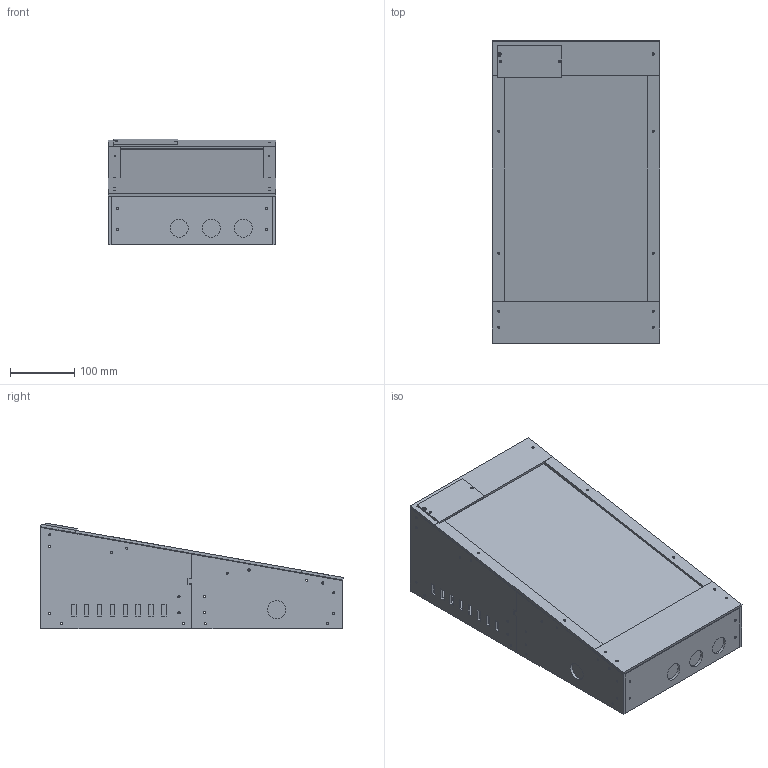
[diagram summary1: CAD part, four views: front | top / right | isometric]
STEP (ISO 10303-21) file: header records copied from the file, then geometry measured from it (millimetres).
FILE_DESCRIPTION(('Open CASCADE Model'),'2;1');
FILE_NAME('Open CASCADE Shape Model','2026-10-30T01:53:43',('Author'),( 'Open CASCADE'),'Open CASCADE STEP processor 7.8','Open CASCADE 7.8' ,'Unknown');
FILE_SCHEMA(('AUTOMOTIVE_DESIGN { 1 0 10303 214 1 1 1 1 }'));
Length unit declared in the file: millimetre
Products named in the file (55): Mini_VPin_Prototype_V1_3; left_front_wall; left_rear_wall; right_front_wall; right_rear_wall; front_button_panel; rear_vent_panel; corner_left_front_24; corner_left_front_56; corner_left_rear_24; corner_left_rear_128; corner_right_front_24; corner_right_front_56; corner_right_rear_24; corner_right_rear_128; splice_left; splice_right; floor_block_left_28; floor_block_left_218; floor_block_left_252; floor_block_left_442; floor_block_right_28; floor_block_right_218; floor_block_right_252; floor_block_right_442; bottom_front; bottom_rear; top_block_left_25; top_block_left_50; top_block_left_140; top_block_left_330; top_block_left_450; top_block_right_25; top_block_right_50; top_block_right_140; top_block_right_330; top_block_right_450; monitor_saddle_left_180; monitor_saddle_left_360; monitor_saddle_right_180 ...
Assembly tree (54 placements, depth 2):
  Mini_VPin_Prototype_V1_3
    left_front_wall
    left_rear_wall
    right_front_wall
    right_rear_wall
    front_button_panel
    rear_vent_panel
    corner_left_front_24
    corner_left_front_56
    corner_left_rear_24
    corner_left_rear_128
    corner_right_front_24
    corner_right_front_56
    corner_right_rear_24
    corner_right_rear_128
    splice_left
    splice_right
    floor_block_left_28
    floor_block_left_218
    floor_block_left_252
    floor_block_left_442
    floor_block_right_28
    floor_block_right_218
    floor_block_right_252
    floor_block_right_442
    bottom_front
    bottom_rear
    top_block_left_25
    top_block_left_50
    top_block_left_140
    top_block_left_330
    top_block_left_450
    top_block_right_25
    top_block_right_50
    top_block_right_140
    top_block_right_330
    top_block_right_450
    monitor_saddle_left_180
    monitor_saddle_left_360
    monitor_saddle_right_180
    monitor_saddle_right_360
    bezel_left_one_piece
    bezel_right_a1_a2
    front_cable_lid
    rear_control_deck
    control_hatch
    REFERENCE_monitor_12mm_envelope
    REFERENCE_PC_allowance_ports_face_front
    REFERENCE_0_front_button_110
    REFERENCE_1_front_button_160
    REFERENCE_2_front_button_210
    REFERENCE_3_left_flipper
    REFERENCE_4_right_flipper
    REFERENCE_5_central_folded_cover_reserve
    REFERENCE_6_USB_encoder_allowance
Bounding box: 260 x 470.69 x 164.59 mm (x, y, z)
Volume: 6493343.1 mm3; surface area: 1288117.8 mm2
Topology: 54 solids, 54 shells, 789 faces, 2001 edges, 1334 vertices
Faces by surface type: plane 651, cylinder 138
Full cylindrical faces by diameter (mm): 3.4 x132, 28 x5
Entity records: 51330 total; most frequent: CARTESIAN_POINT 9271, DIRECTION 7328, LINE 4793, VECTOR 4793, ORIENTED_EDGE 4002, PCURVE 4002, DEFINITIONAL_REPRESENTATION 4002, EDGE_CURVE 2001
One B-rep face of a CAD part: STEP entity #52242.
In plain terms, the planar face has unit normal (0, -0.174, 0.985).
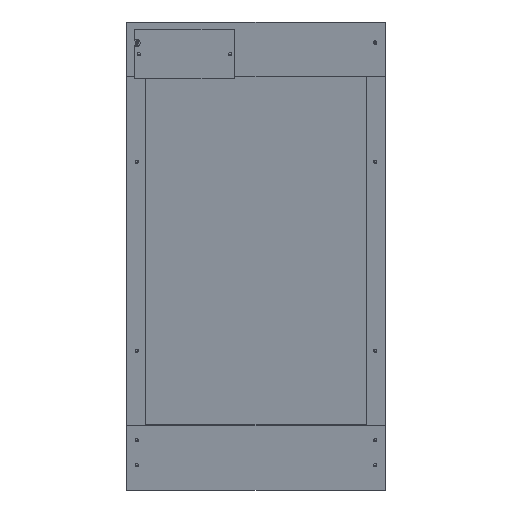
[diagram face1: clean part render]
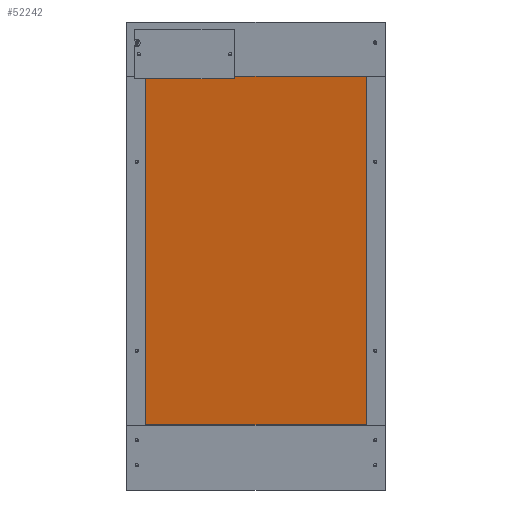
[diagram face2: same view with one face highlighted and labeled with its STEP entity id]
Its self-contained STEP definition (entity closure, numbers rounded to 3 decimals):
#52073 = PLANE('',#52074);
#52074 = AXIS2_PLACEMENT_3D('',#52075,#52076,#52077);
#52075 = CARTESIAN_POINT('',(18.1,64.,86.285));
#52076 = DIRECTION('',(-0.,1.,0.));
#52077 = DIRECTION('',(0.,0.,-1.));
#52101 = PLANE('',#52102);
#52102 = AXIS2_PLACEMENT_3D('',#52103,#52104,#52105);
#52103 = CARTESIAN_POINT('',(241.9,240.675,111.437));
#52104 = DIRECTION('',(1.,0.,0.));
#52105 = DIRECTION('',(-0.,0.,1.));
#52129 = PLANE('',#52130);
#52130 = AXIS2_PLACEMENT_3D('',#52131,#52132,#52133);
#52131 = CARTESIAN_POINT('',(18.1,417.349,136.59));
#52132 = DIRECTION('',(0.,-1.,0.));
#52133 = DIRECTION('',(0.,0.,1.));
#52155 = PLANE('',#52156);
#52156 = AXIS2_PLACEMENT_3D('',#52157,#52158,#52159);
#52157 = CARTESIAN_POINT('',(18.1,240.675,111.437));
#52158 = DIRECTION('',(1.,0.,0.));
#52159 = DIRECTION('',(-0.,0.,1.));
#52172 = VERTEX_POINT('',#52173);
#52173 = CARTESIAN_POINT('',(241.9,417.349,148.59));
#52194 = EDGE_CURVE('',#52195,#52172,#52197,.T.);
#52195 = VERTEX_POINT('',#52196);
#52196 = CARTESIAN_POINT('',(18.1,417.349,148.59));
#52197 = SURFACE_CURVE('',#52198,(#52202,#52209),.PCURVE_S1.);
#52198 = LINE('',#52199,#52200);
#52199 = CARTESIAN_POINT('',(18.1,417.349,148.59));
#52200 = VECTOR('',#52201,1.);
#52201 = DIRECTION('',(1.,0.,0.));
#52202 = PCURVE('',#52129,#52203);
#52203 = DEFINITIONAL_REPRESENTATION('',(#52204),#52208);
#52204 = LINE('',#52205,#52206);
#52205 = CARTESIAN_POINT('',(12.,0.));
#52206 = VECTOR('',#52207,1.);
#52207 = DIRECTION('',(0.,-1.));
#52208 = ( GEOMETRIC_REPRESENTATION_CONTEXT(2) 
PARAMETRIC_REPRESENTATION_CONTEXT() REPRESENTATION_CONTEXT('2D SPACE',''
  ) );
#52209 = PCURVE('',#52210,#52215);
#52210 = PLANE('',#52211);
#52211 = AXIS2_PLACEMENT_3D('',#52212,#52213,#52214);
#52212 = CARTESIAN_POINT('',(18.1,417.349,148.59));
#52213 = DIRECTION('',(0.,0.174,-0.985));
#52214 = DIRECTION('',(0.,-0.985,-0.174));
#52215 = DEFINITIONAL_REPRESENTATION('',(#52216),#52220);
#52216 = LINE('',#52217,#52218);
#52217 = CARTESIAN_POINT('',(0.,0.));
#52218 = VECTOR('',#52219,1.);
#52219 = DIRECTION('',(0.,-1.));
#52220 = ( GEOMETRIC_REPRESENTATION_CONTEXT(2) 
PARAMETRIC_REPRESENTATION_CONTEXT() REPRESENTATION_CONTEXT('2D SPACE',''
  ) );
#52242 = ADVANCED_FACE('',(#52243),#52210,.F.);
#52243 = FACE_BOUND('',#52244,.F.);
#52244 = EDGE_LOOP('',(#52245,#52246,#52269,#52292));
#52245 = ORIENTED_EDGE('',*,*,#52194,.T.);
#52246 = ORIENTED_EDGE('',*,*,#52247,.T.);
#52247 = EDGE_CURVE('',#52172,#52248,#52250,.T.);
#52248 = VERTEX_POINT('',#52249);
#52249 = CARTESIAN_POINT('',(241.9,64.,86.285));
#52250 = SURFACE_CURVE('',#52251,(#52255,#52262),.PCURVE_S1.);
#52251 = LINE('',#52252,#52253);
#52252 = CARTESIAN_POINT('',(241.9,417.349,148.59));
#52253 = VECTOR('',#52254,1.);
#52254 = DIRECTION('',(0.,-0.985,-0.174));
#52255 = PCURVE('',#52210,#52256);
#52256 = DEFINITIONAL_REPRESENTATION('',(#52257),#52261);
#52257 = LINE('',#52258,#52259);
#52258 = CARTESIAN_POINT('',(0.,-223.8));
#52259 = VECTOR('',#52260,1.);
#52260 = DIRECTION('',(1.,0.));
#52261 = ( GEOMETRIC_REPRESENTATION_CONTEXT(2) 
PARAMETRIC_REPRESENTATION_CONTEXT() REPRESENTATION_CONTEXT('2D SPACE',''
  ) );
#52262 = PCURVE('',#52101,#52263);
#52263 = DEFINITIONAL_REPRESENTATION('',(#52264),#52268);
#52264 = LINE('',#52265,#52266);
#52265 = CARTESIAN_POINT('',(37.152,-176.675));
#52266 = VECTOR('',#52267,1.);
#52267 = DIRECTION('',(-0.174,0.985));
#52268 = ( GEOMETRIC_REPRESENTATION_CONTEXT(2) 
PARAMETRIC_REPRESENTATION_CONTEXT() REPRESENTATION_CONTEXT('2D SPACE',''
  ) );
#52269 = ORIENTED_EDGE('',*,*,#52270,.F.);
#52270 = EDGE_CURVE('',#52271,#52248,#52273,.T.);
#52271 = VERTEX_POINT('',#52272);
#52272 = CARTESIAN_POINT('',(18.1,64.,86.285));
#52273 = SURFACE_CURVE('',#52274,(#52278,#52285),.PCURVE_S1.);
#52274 = LINE('',#52275,#52276);
#52275 = CARTESIAN_POINT('',(18.1,64.,86.285));
#52276 = VECTOR('',#52277,1.);
#52277 = DIRECTION('',(1.,0.,0.));
#52278 = PCURVE('',#52210,#52279);
#52279 = DEFINITIONAL_REPRESENTATION('',(#52280),#52284);
#52280 = LINE('',#52281,#52282);
#52281 = CARTESIAN_POINT('',(358.8,0.));
#52282 = VECTOR('',#52283,1.);
#52283 = DIRECTION('',(0.,-1.));
#52284 = ( GEOMETRIC_REPRESENTATION_CONTEXT(2) 
PARAMETRIC_REPRESENTATION_CONTEXT() REPRESENTATION_CONTEXT('2D SPACE',''
  ) );
#52285 = PCURVE('',#52073,#52286);
#52286 = DEFINITIONAL_REPRESENTATION('',(#52287),#52291);
#52287 = LINE('',#52288,#52289);
#52288 = CARTESIAN_POINT('',(0.,0.));
#52289 = VECTOR('',#52290,1.);
#52290 = DIRECTION('',(0.,-1.));
#52291 = ( GEOMETRIC_REPRESENTATION_CONTEXT(2) 
PARAMETRIC_REPRESENTATION_CONTEXT() REPRESENTATION_CONTEXT('2D SPACE',''
  ) );
#52292 = ORIENTED_EDGE('',*,*,#52293,.F.);
#52293 = EDGE_CURVE('',#52195,#52271,#52294,.T.);
#52294 = SURFACE_CURVE('',#52295,(#52299,#52306),.PCURVE_S1.);
#52295 = LINE('',#52296,#52297);
#52296 = CARTESIAN_POINT('',(18.1,417.349,148.59));
#52297 = VECTOR('',#52298,1.);
#52298 = DIRECTION('',(0.,-0.985,-0.174));
#52299 = PCURVE('',#52210,#52300);
#52300 = DEFINITIONAL_REPRESENTATION('',(#52301),#52305);
#52301 = LINE('',#52302,#52303);
#52302 = CARTESIAN_POINT('',(0.,0.));
#52303 = VECTOR('',#52304,1.);
#52304 = DIRECTION('',(1.,0.));
#52305 = ( GEOMETRIC_REPRESENTATION_CONTEXT(2) 
PARAMETRIC_REPRESENTATION_CONTEXT() REPRESENTATION_CONTEXT('2D SPACE',''
  ) );
#52306 = PCURVE('',#52155,#52307);
#52307 = DEFINITIONAL_REPRESENTATION('',(#52308),#52312);
#52308 = LINE('',#52309,#52310);
#52309 = CARTESIAN_POINT('',(37.152,-176.675));
#52310 = VECTOR('',#52311,1.);
#52311 = DIRECTION('',(-0.174,0.985));
#52312 = ( GEOMETRIC_REPRESENTATION_CONTEXT(2) 
PARAMETRIC_REPRESENTATION_CONTEXT() REPRESENTATION_CONTEXT('2D SPACE',''
  ) );
